VERSION 5.8 ;
BUSBITCHARS "[]" ;
DIVIDERCHAR "/" ;

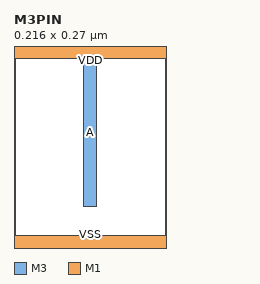
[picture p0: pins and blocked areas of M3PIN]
MACRO M3PIN
  CLASS CORE ;
  ORIGIN 0 0 ;
  FOREIGN M3PIN 0 0 ;
  SIZE 0.216 BY 0.27 ;
  SYMMETRY X Y ;
  SITE asap7sc7p5t ;
  PIN A
    DIRECTION INPUT ;
    USE SIGNAL ;
    PORT
      LAYER M3 ;
        RECT 0.099 0.05 0.117 0.26 ;
    END
  END A
  PIN VDD
    DIRECTION INOUT ;
    USE POWER ;
    SHAPE ABUTMENT ;
    PORT
      LAYER M1 ;
        RECT 0 0.261 0.216 0.279 ;
    END
  END VDD
  PIN VSS
    DIRECTION INOUT ;
    USE GROUND ;
    SHAPE ABUTMENT ;
    PORT
      LAYER M1 ;
        RECT 0 -0.009 0.216 0.009 ;
    END
  END VSS
END M3PIN

END LIBRARY
